VERSION 5.7 ;
  NOWIREEXTENSIONATPIN ON ;
  DIVIDERCHAR "/" ;
  BUSBITCHARS "[]" ;
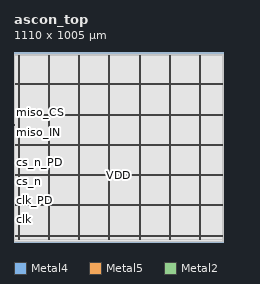
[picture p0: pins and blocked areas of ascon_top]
MACRO ascon_top
  CLASS BLOCK ;
  FOREIGN ascon_top ;
  ORIGIN 0.000 0.000 ;
  SIZE 1110.000 BY 1005.000 ;
  PIN VDD
    DIRECTION INOUT ;
    USE POWER ;
    PORT
      LAYER Metal4 ;
        RECT 22.240 15.380 23.840 988.140 ;
    END
    PORT
      LAYER Metal4 ;
        RECT 182.240 15.380 183.840 988.140 ;
    END
    PORT
      LAYER Metal4 ;
        RECT 342.240 15.380 343.840 988.140 ;
    END
    PORT
      LAYER Metal4 ;
        RECT 502.240 15.380 503.840 988.140 ;
    END
    PORT
      LAYER Metal4 ;
        RECT 662.240 15.380 663.840 988.140 ;
    END
    PORT
      LAYER Metal4 ;
        RECT 822.240 15.380 823.840 988.140 ;
    END
    PORT
      LAYER Metal4 ;
        RECT 982.240 15.380 983.840 988.140 ;
    END
    PORT
      LAYER Metal5 ;
        RECT 6.720 31.530 1103.200 33.130 ;
    END
    PORT
      LAYER Metal5 ;
        RECT 6.720 191.530 1103.200 193.130 ;
    END
    PORT
      LAYER Metal5 ;
        RECT 6.720 351.530 1103.200 353.130 ;
    END
    PORT
      LAYER Metal5 ;
        RECT 6.720 511.530 1103.200 513.130 ;
    END
    PORT
      LAYER Metal5 ;
        RECT 6.720 671.530 1103.200 673.130 ;
    END
    PORT
      LAYER Metal5 ;
        RECT 6.720 831.530 1103.200 833.130 ;
    END
  END VDD
  PIN VSS
    DIRECTION INOUT ;
    USE GROUND ;
    PORT
      LAYER Metal4 ;
        RECT 25.540 15.380 27.140 988.140 ;
    END
    PORT
      LAYER Metal4 ;
        RECT 185.540 15.380 187.140 988.140 ;
    END
    PORT
      LAYER Metal4 ;
        RECT 345.540 15.380 347.140 988.140 ;
    END
    PORT
      LAYER Metal4 ;
        RECT 505.540 15.380 507.140 988.140 ;
    END
    PORT
      LAYER Metal4 ;
        RECT 665.540 15.380 667.140 988.140 ;
    END
    PORT
      LAYER Metal4 ;
        RECT 825.540 15.380 827.140 988.140 ;
    END
    PORT
      LAYER Metal4 ;
        RECT 985.540 15.380 987.140 988.140 ;
    END
    PORT
      LAYER Metal5 ;
        RECT 6.720 34.830 1103.200 36.430 ;
    END
    PORT
      LAYER Metal5 ;
        RECT 6.720 194.830 1103.200 196.430 ;
    END
    PORT
      LAYER Metal5 ;
        RECT 6.720 354.830 1103.200 356.430 ;
    END
    PORT
      LAYER Metal5 ;
        RECT 6.720 514.830 1103.200 516.430 ;
    END
    PORT
      LAYER Metal5 ;
        RECT 6.720 674.830 1103.200 676.430 ;
    END
    PORT
      LAYER Metal5 ;
        RECT 6.720 834.830 1103.200 836.430 ;
    END
  END VSS
  PIN clk
    DIRECTION INPUT ;
    USE SIGNAL ;
    ANTENNAGATEAREA 4.738000 ;
    PORT
      LAYER Metal2 ;
        RECT 0.000 118.760 1.000 119.140 ;
    END
  END clk
  PIN clk_PD
    DIRECTION OUTPUT ;
    USE SIGNAL ;
    ANTENNADIFFAREA 0.360800 ;
    PORT
      LAYER Metal2 ;
        RECT 0.000 179.290 1.000 179.670 ;
    END
  END clk_PD
  PIN clk_PU
    DIRECTION OUTPUT ;
    USE SIGNAL ;
    ANTENNADIFFAREA 0.360800 ;
    PORT
      LAYER Metal2 ;
        RECT 0.000 183.655 1.000 184.035 ;
    END
  END clk_PU
  PIN cs_n
    DIRECTION INPUT ;
    USE SIGNAL ;
    ANTENNAGATEAREA 0.396000 ;
    PORT
      LAYER Metal2 ;
        RECT 0.000 318.760 1.000 319.140 ;
    END
  END cs_n
  PIN cs_n_PD
    DIRECTION OUTPUT ;
    USE SIGNAL ;
    ANTENNADIFFAREA 0.360800 ;
    PORT
      LAYER Metal2 ;
        RECT 0.000 379.290 1.000 379.670 ;
    END
  END cs_n_PD
  PIN cs_n_PU
    DIRECTION OUTPUT ;
    USE SIGNAL ;
    ANTENNADIFFAREA 0.360800 ;
    PORT
      LAYER Metal2 ;
        RECT 0.000 383.655 1.000 384.035 ;
    END
  END cs_n_PU
  PIN miso_CS
    DIRECTION OUTPUT ;
    USE SIGNAL ;
    ANTENNADIFFAREA 0.360800 ;
    PORT
      LAYER Metal2 ;
        RECT 0.000 686.260 1.000 686.640 ;
    END
  END miso_CS
  PIN miso_IE
    DIRECTION OUTPUT ;
    USE SIGNAL ;
    ANTENNADIFFAREA 0.360800 ;
    PORT
      LAYER Metal2 ;
        RECT 0.000 678.235 1.000 678.615 ;
    END
  END miso_IE
  PIN miso_IN
    DIRECTION INPUT ;
    USE SIGNAL ;
    ANTENNAGATEAREA 0.498500 ;
    PORT
      LAYER Metal2 ;
        RECT 0.000 618.760 1.000 619.140 ;
    END
  END miso_IN
  PIN miso_OE
    DIRECTION OUTPUT ;
    USE SIGNAL ;
    ANTENNADIFFAREA 0.536800 ;
    PORT
      LAYER Metal2 ;
        RECT 0.000 619.490 1.000 619.870 ;
    END
  END miso_OE
  PIN miso_OUT
    DIRECTION OUTPUT ;
    USE SIGNAL ;
    ANTENNADIFFAREA 2.080400 ;
    PORT
      LAYER Metal2 ;
        RECT 0.000 620.220 1.000 620.600 ;
    END
  END miso_OUT
  PIN miso_PD
    DIRECTION OUTPUT ;
    USE SIGNAL ;
    ANTENNADIFFAREA 0.360800 ;
    PORT
      LAYER Metal2 ;
        RECT 0.000 679.290 1.000 679.670 ;
    END
  END miso_PD
  PIN miso_PDRV0
    DIRECTION OUTPUT ;
    USE SIGNAL ;
    ANTENNADIFFAREA 0.536800 ;
    PORT
      LAYER Metal2 ;
        RECT 0.000 682.510 1.000 682.890 ;
    END
  END miso_PDRV0
  PIN miso_PDRV1
    DIRECTION OUTPUT ;
    USE SIGNAL ;
    ANTENNADIFFAREA 0.360800 ;
    PORT
      LAYER Metal2 ;
        RECT 0.000 681.800 1.000 682.180 ;
    END
  END miso_PDRV1
  PIN miso_PU
    DIRECTION OUTPUT ;
    USE SIGNAL ;
    ANTENNADIFFAREA 0.360800 ;
    PORT
      LAYER Metal2 ;
        RECT 0.000 683.655 1.000 684.035 ;
    END
  END miso_PU
  PIN miso_SL
    DIRECTION OUTPUT ;
    USE SIGNAL ;
    ANTENNADIFFAREA 0.360800 ;
    PORT
      LAYER Metal2 ;
        RECT 0.000 620.950 1.000 621.330 ;
    END
  END miso_SL
  PIN mosi
    DIRECTION INPUT ;
    USE SIGNAL ;
    ANTENNAGATEAREA 0.396000 ;
    PORT
      LAYER Metal2 ;
        RECT 0.000 518.760 1.000 519.140 ;
    END
  END mosi
  PIN mosi_PD
    DIRECTION OUTPUT ;
    USE SIGNAL ;
    ANTENNADIFFAREA 0.360800 ;
    PORT
      LAYER Metal2 ;
        RECT 0.000 579.290 1.000 579.670 ;
    END
  END mosi_PD
  PIN mosi_PU
    DIRECTION OUTPUT ;
    USE SIGNAL ;
    ANTENNADIFFAREA 0.360800 ;
    PORT
      LAYER Metal2 ;
        RECT 0.000 583.655 1.000 584.035 ;
    END
  END mosi_PU
  PIN rst
    DIRECTION INPUT ;
    USE SIGNAL ;
    ANTENNAGATEAREA 1.102000 ;
    PORT
      LAYER Metal2 ;
        RECT 0.000 218.760 1.000 219.140 ;
    END
  END rst
  PIN rst_PD
    DIRECTION OUTPUT ;
    USE SIGNAL ;
    ANTENNADIFFAREA 0.360800 ;
    PORT
      LAYER Metal2 ;
        RECT 0.000 279.290 1.000 279.670 ;
    END
  END rst_PD
  PIN rst_PU
    DIRECTION OUTPUT ;
    USE SIGNAL ;
    ANTENNADIFFAREA 0.360800 ;
    PORT
      LAYER Metal2 ;
        RECT 0.000 283.655 1.000 284.035 ;
    END
  END rst_PU
  PIN sclk
    DIRECTION INPUT ;
    USE SIGNAL ;
    ANTENNAGATEAREA 0.396000 ;
    PORT
      LAYER Metal2 ;
        RECT 0.000 418.760 1.000 419.140 ;
    END
  END sclk
  PIN sclk_PD
    DIRECTION OUTPUT ;
    USE SIGNAL ;
    ANTENNADIFFAREA 0.360800 ;
    PORT
      LAYER Metal2 ;
        RECT 0.000 479.290 1.000 479.670 ;
    END
  END sclk_PD
  PIN sclk_PU
    DIRECTION OUTPUT ;
    USE SIGNAL ;
    ANTENNADIFFAREA 0.360800 ;
    PORT
      LAYER Metal2 ;
        RECT 0.000 483.655 1.000 484.035 ;
    END
  END sclk_PU
  OBS
      LAYER Nwell ;
        RECT 6.290 15.250 1103.630 988.270 ;
      LAYER Metal1 ;
        RECT 6.720 15.380 1103.200 988.140 ;
      LAYER Metal2 ;
        RECT 0.140 686.940 1107.540 993.910 ;
        RECT 1.300 685.960 1107.540 686.940 ;
        RECT 0.140 684.335 1107.540 685.960 ;
        RECT 1.300 683.355 1107.540 684.335 ;
        RECT 0.140 683.190 1107.540 683.355 ;
        RECT 1.300 681.500 1107.540 683.190 ;
        RECT 0.140 679.970 1107.540 681.500 ;
        RECT 1.300 678.990 1107.540 679.970 ;
        RECT 0.140 678.915 1107.540 678.990 ;
        RECT 1.300 677.935 1107.540 678.915 ;
        RECT 0.140 621.630 1107.540 677.935 ;
        RECT 1.300 618.460 1107.540 621.630 ;
        RECT 0.140 584.335 1107.540 618.460 ;
        RECT 1.300 583.355 1107.540 584.335 ;
        RECT 0.140 579.970 1107.540 583.355 ;
        RECT 1.300 578.990 1107.540 579.970 ;
        RECT 0.140 519.440 1107.540 578.990 ;
        RECT 1.300 518.460 1107.540 519.440 ;
        RECT 0.140 484.335 1107.540 518.460 ;
        RECT 1.300 483.355 1107.540 484.335 ;
        RECT 0.140 479.970 1107.540 483.355 ;
        RECT 1.300 478.990 1107.540 479.970 ;
        RECT 0.140 419.440 1107.540 478.990 ;
        RECT 1.300 418.460 1107.540 419.440 ;
        RECT 0.140 384.335 1107.540 418.460 ;
        RECT 1.300 383.355 1107.540 384.335 ;
        RECT 0.140 379.970 1107.540 383.355 ;
        RECT 1.300 378.990 1107.540 379.970 ;
        RECT 0.140 319.440 1107.540 378.990 ;
        RECT 1.300 318.460 1107.540 319.440 ;
        RECT 0.140 284.335 1107.540 318.460 ;
        RECT 1.300 283.355 1107.540 284.335 ;
        RECT 0.140 279.970 1107.540 283.355 ;
        RECT 1.300 278.990 1107.540 279.970 ;
        RECT 0.140 219.440 1107.540 278.990 ;
        RECT 1.300 218.460 1107.540 219.440 ;
        RECT 0.140 184.335 1107.540 218.460 ;
        RECT 1.300 183.355 1107.540 184.335 ;
        RECT 0.140 179.970 1107.540 183.355 ;
        RECT 1.300 178.990 1107.540 179.970 ;
        RECT 0.140 119.440 1107.540 178.990 ;
        RECT 1.300 118.460 1107.540 119.440 ;
        RECT 0.140 4.010 1107.540 118.460 ;
      LAYER Metal3 ;
        RECT 0.090 4.060 1107.590 993.860 ;
      LAYER Metal4 ;
        RECT 0.700 988.440 1101.940 991.110 ;
        RECT 0.700 15.080 21.940 988.440 ;
        RECT 24.140 15.080 25.240 988.440 ;
        RECT 27.440 15.080 181.940 988.440 ;
        RECT 184.140 15.080 185.240 988.440 ;
        RECT 187.440 15.080 341.940 988.440 ;
        RECT 344.140 15.080 345.240 988.440 ;
        RECT 347.440 15.080 501.940 988.440 ;
        RECT 504.140 15.080 505.240 988.440 ;
        RECT 507.440 15.080 661.940 988.440 ;
        RECT 664.140 15.080 665.240 988.440 ;
        RECT 667.440 15.080 821.940 988.440 ;
        RECT 824.140 15.080 825.240 988.440 ;
        RECT 827.440 15.080 981.940 988.440 ;
        RECT 984.140 15.080 985.240 988.440 ;
        RECT 987.440 15.080 1101.940 988.440 ;
        RECT 0.700 4.010 1101.940 15.080 ;
  END
END ascon_top
END LIBRARY

